VERSION 5.6 ;
BUSBITCHARS "[]" ;
DIVIDERCHAR "/" ;

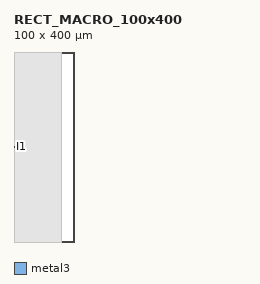
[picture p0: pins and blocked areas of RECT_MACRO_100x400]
MACRO RECT_MACRO_100x400
  CLASS BLOCK ;
  FOREIGN RECT_MACRO_100x400 0 0 ;
  ORIGIN 0 0 ;
  SYMMETRY X Y R90 ;
  SIZE 100 BY 400 ;
  PIN I1
    DIRECTION INPUT ;
    PORT
      LAYER metal3 ;
        RECT 0 200 0.140 200.070 ;
    END
  END I1
  OBS
    LAYER metal1 ;
      RECT 0 0 100 400 ;
  END
END RECT_MACRO_100x400

END LIBRARY
